VERSION 5.8 ;
BUSBITCHARS "[]" ;
DIVIDERCHAR "/" ;
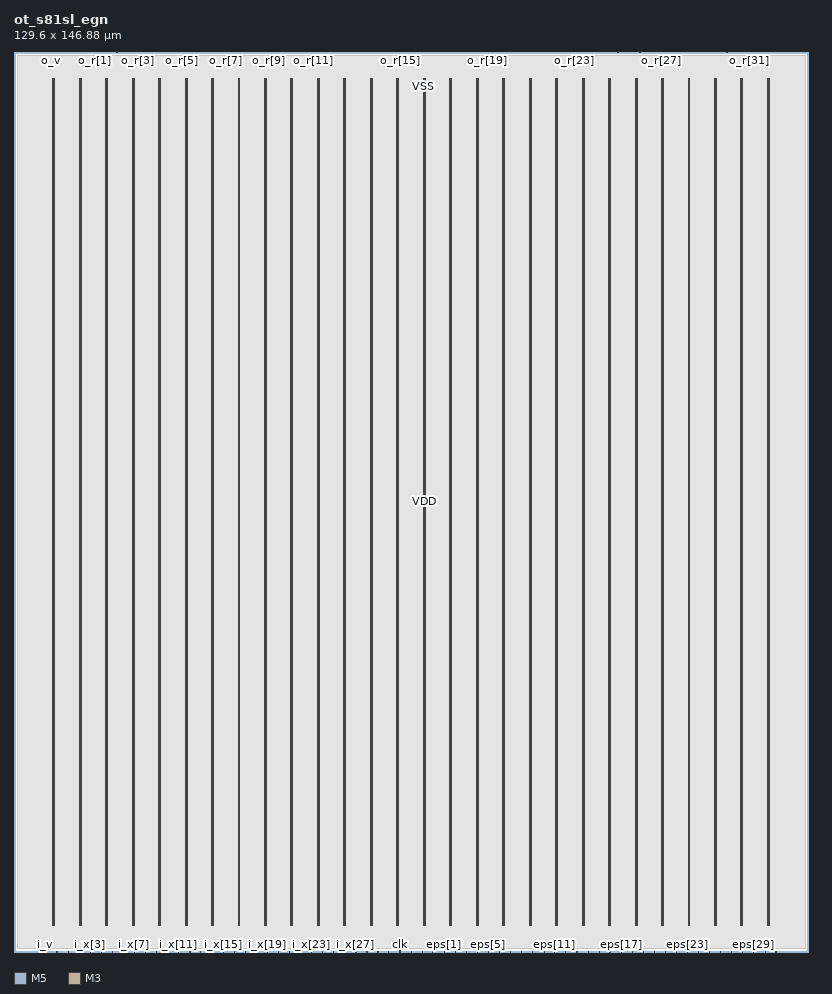
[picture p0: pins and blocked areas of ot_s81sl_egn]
MACRO ot_s81sl_egn
  CLASS BLOCK ;
  ORIGIN 0 0 ;
  FOREIGN ot_s81sl_egn 0 0 ;
  SIZE 129.600 BY 146.880 ;
  SYMMETRY X Y ;
  PIN clk
    DIRECTION INPUT ;
    USE SIGNAL ;
    PORT
      LAYER M5 ;
        RECT 62.9640 0.0000 63.0120 0.4800 ;
    END
  END clk
  PIN eps[0]
    DIRECTION INPUT ;
    USE SIGNAL ;
    PORT
      LAYER M5 ;
        RECT 68.3520 0.0000 68.3760 0.0840 ;
    END
  END eps[0]
  PIN eps[10]
    DIRECTION INPUT ;
    USE SIGNAL ;
    PORT
      LAYER M5 ;
        RECT 86.4960 0.0000 86.5200 0.0840 ;
    END
  END eps[10]
  PIN eps[11]
    DIRECTION INPUT ;
    USE SIGNAL ;
    PORT
      LAYER M3 ;
        RECT 88.2720 0.0000 88.2900 0.0380 ;
    END
  END eps[11]
  PIN eps[12]
    DIRECTION INPUT ;
    USE SIGNAL ;
    PORT
      LAYER M5 ;
        RECT 90.0480 0.0000 90.0720 0.0840 ;
    END
  END eps[12]
  PIN eps[13]
    DIRECTION INPUT ;
    USE SIGNAL ;
    PORT
      LAYER M3 ;
        RECT 91.8720 0.0000 91.8900 0.0380 ;
    END
  END eps[13]
  PIN eps[14]
    DIRECTION INPUT ;
    USE SIGNAL ;
    PORT
      LAYER M5 ;
        RECT 93.6960 0.0000 93.7200 0.0840 ;
    END
  END eps[14]
  PIN eps[15]
    DIRECTION INPUT ;
    USE SIGNAL ;
    PORT
      LAYER M3 ;
        RECT 95.4720 0.0000 95.4900 0.0380 ;
    END
  END eps[15]
  PIN eps[16]
    DIRECTION INPUT ;
    USE SIGNAL ;
    PORT
      LAYER M5 ;
        RECT 97.2480 0.0000 97.2720 0.0840 ;
    END
  END eps[16]
  PIN eps[17]
    DIRECTION INPUT ;
    USE SIGNAL ;
    PORT
      LAYER M3 ;
        RECT 99.0720 0.0000 99.0900 0.0380 ;
    END
  END eps[17]
  PIN eps[18]
    DIRECTION INPUT ;
    USE SIGNAL ;
    PORT
      LAYER M5 ;
        RECT 100.8960 0.0000 100.9200 0.0840 ;
    END
  END eps[18]
  PIN eps[19]
    DIRECTION INPUT ;
    USE SIGNAL ;
    PORT
      LAYER M3 ;
        RECT 102.6720 0.0000 102.6900 0.0380 ;
    END
  END eps[19]
  PIN eps[1]
    DIRECTION INPUT ;
    USE SIGNAL ;
    PORT
      LAYER M3 ;
        RECT 70.2000 0.0000 70.2180 0.0380 ;
    END
  END eps[1]
  PIN eps[20]
    DIRECTION INPUT ;
    USE SIGNAL ;
    PORT
      LAYER M5 ;
        RECT 104.5440 0.0000 104.5680 0.0840 ;
    END
  END eps[20]
  PIN eps[21]
    DIRECTION INPUT ;
    USE SIGNAL ;
    PORT
      LAYER M3 ;
        RECT 106.3440 0.0000 106.3620 0.0380 ;
    END
  END eps[21]
  PIN eps[22]
    DIRECTION INPUT ;
    USE SIGNAL ;
    PORT
      LAYER M5 ;
        RECT 108.0960 0.0000 108.1200 0.0840 ;
    END
  END eps[22]
  PIN eps[23]
    DIRECTION INPUT ;
    USE SIGNAL ;
    PORT
      LAYER M3 ;
        RECT 109.9440 0.0000 109.9620 0.0380 ;
    END
  END eps[23]
  PIN eps[24]
    DIRECTION INPUT ;
    USE SIGNAL ;
    PORT
      LAYER M5 ;
        RECT 111.7440 0.0000 111.7680 0.0840 ;
    END
  END eps[24]
  PIN eps[25]
    DIRECTION INPUT ;
    USE SIGNAL ;
    PORT
      LAYER M3 ;
        RECT 113.5440 0.0000 113.5620 0.0380 ;
    END
  END eps[25]
  PIN eps[26]
    DIRECTION INPUT ;
    USE SIGNAL ;
    PORT
      LAYER M5 ;
        RECT 115.2960 0.0000 115.3200 0.0840 ;
    END
  END eps[26]
  PIN eps[27]
    DIRECTION INPUT ;
    USE SIGNAL ;
    PORT
      LAYER M3 ;
        RECT 117.1440 0.0000 117.1620 0.0380 ;
    END
  END eps[27]
  PIN eps[28]
    DIRECTION INPUT ;
    USE SIGNAL ;
    PORT
      LAYER M5 ;
        RECT 118.9440 0.0000 118.9680 0.0840 ;
    END
  END eps[28]
  PIN eps[29]
    DIRECTION INPUT ;
    USE SIGNAL ;
    PORT
      LAYER M3 ;
        RECT 120.7440 0.0000 120.7620 0.0380 ;
    END
  END eps[29]
  PIN eps[2]
    DIRECTION INPUT ;
    USE SIGNAL ;
    PORT
      LAYER M5 ;
        RECT 72.0000 0.0000 72.0240 0.0840 ;
    END
  END eps[2]
  PIN eps[30]
    DIRECTION INPUT ;
    USE SIGNAL ;
    PORT
      LAYER M5 ;
        RECT 122.5920 0.0000 122.6160 0.0840 ;
    END
  END eps[30]
  PIN eps[31]
    DIRECTION INPUT ;
    USE SIGNAL ;
    PORT
      LAYER M3 ;
        RECT 124.3440 0.0000 124.3620 0.0380 ;
    END
  END eps[31]
  PIN eps[3]
    DIRECTION INPUT ;
    USE SIGNAL ;
    PORT
      LAYER M3 ;
        RECT 73.8000 0.0000 73.8180 0.0380 ;
    END
  END eps[3]
  PIN eps[4]
    DIRECTION INPUT ;
    USE SIGNAL ;
    PORT
      LAYER M5 ;
        RECT 75.6480 0.0000 75.6720 0.0840 ;
    END
  END eps[4]
  PIN eps[5]
    DIRECTION INPUT ;
    USE SIGNAL ;
    PORT
      LAYER M3 ;
        RECT 77.4000 0.0000 77.4180 0.0380 ;
    END
  END eps[5]
  PIN eps[6]
    DIRECTION INPUT ;
    USE SIGNAL ;
    PORT
      LAYER M5 ;
        RECT 79.2000 0.0000 79.2240 0.0840 ;
    END
  END eps[6]
  PIN eps[7]
    DIRECTION INPUT ;
    USE SIGNAL ;
    PORT
      LAYER M3 ;
        RECT 81.0720 0.0000 81.0900 0.0380 ;
    END
  END eps[7]
  PIN eps[8]
    DIRECTION INPUT ;
    USE SIGNAL ;
    PORT
      LAYER M5 ;
        RECT 82.8480 0.0000 82.8720 0.0840 ;
    END
  END eps[8]
  PIN eps[9]
    DIRECTION INPUT ;
    USE SIGNAL ;
    PORT
      LAYER M3 ;
        RECT 84.6720 0.0000 84.6900 0.0380 ;
    END
  END eps[9]
  PIN i_v
    DIRECTION INPUT ;
    USE SIGNAL ;
    PORT
      LAYER M3 ;
        RECT 5.1840 0.0000 5.2020 0.0380 ;
    END
  END i_v
  PIN i_x[0]
    DIRECTION INPUT ;
    USE SIGNAL ;
    PORT
      LAYER M5 ;
        RECT 7.0080 0.0000 7.0320 0.0840 ;
    END
  END i_x[0]
  PIN i_x[10]
    DIRECTION INPUT ;
    USE SIGNAL ;
    PORT
      LAYER M5 ;
        RECT 25.0560 0.0000 25.0800 0.0840 ;
    END
  END i_x[10]
  PIN i_x[11]
    DIRECTION INPUT ;
    USE SIGNAL ;
    PORT
      LAYER M3 ;
        RECT 26.8560 0.0000 26.8740 0.0380 ;
    END
  END i_x[11]
  PIN i_x[12]
    DIRECTION INPUT ;
    USE SIGNAL ;
    PORT
      LAYER M5 ;
        RECT 28.7040 0.0000 28.7280 0.0840 ;
    END
  END i_x[12]
  PIN i_x[13]
    DIRECTION INPUT ;
    USE SIGNAL ;
    PORT
      LAYER M3 ;
        RECT 30.4560 0.0000 30.4740 0.0380 ;
    END
  END i_x[13]
  PIN i_x[14]
    DIRECTION INPUT ;
    USE SIGNAL ;
    PORT
      LAYER M5 ;
        RECT 32.2560 0.0000 32.2800 0.0840 ;
    END
  END i_x[14]
  PIN i_x[15]
    DIRECTION INPUT ;
    USE SIGNAL ;
    PORT
      LAYER M3 ;
        RECT 34.1280 0.0000 34.1460 0.0380 ;
    END
  END i_x[15]
  PIN i_x[16]
    DIRECTION INPUT ;
    USE SIGNAL ;
    PORT
      LAYER M5 ;
        RECT 35.9040 0.0000 35.9280 0.0840 ;
    END
  END i_x[16]
  PIN i_x[17]
    DIRECTION INPUT ;
    USE SIGNAL ;
    PORT
      LAYER M3 ;
        RECT 37.7280 0.0000 37.7460 0.0380 ;
    END
  END i_x[17]
  PIN i_x[18]
    DIRECTION INPUT ;
    USE SIGNAL ;
    PORT
      LAYER M5 ;
        RECT 39.5520 0.0000 39.5760 0.0840 ;
    END
  END i_x[18]
  PIN i_x[19]
    DIRECTION INPUT ;
    USE SIGNAL ;
    PORT
      LAYER M3 ;
        RECT 41.3280 0.0000 41.3460 0.0380 ;
    END
  END i_x[19]
  PIN i_x[1]
    DIRECTION INPUT ;
    USE SIGNAL ;
    PORT
      LAYER M3 ;
        RECT 8.8560 0.0000 8.8740 0.0380 ;
    END
  END i_x[1]
  PIN i_x[20]
    DIRECTION INPUT ;
    USE SIGNAL ;
    PORT
      LAYER M5 ;
        RECT 43.1040 0.0000 43.1280 0.0840 ;
    END
  END i_x[20]
  PIN i_x[21]
    DIRECTION INPUT ;
    USE SIGNAL ;
    PORT
      LAYER M3 ;
        RECT 44.9280 0.0000 44.9460 0.0380 ;
    END
  END i_x[21]
  PIN i_x[22]
    DIRECTION INPUT ;
    USE SIGNAL ;
    PORT
      LAYER M5 ;
        RECT 46.7520 0.0000 46.7760 0.0840 ;
    END
  END i_x[22]
  PIN i_x[23]
    DIRECTION INPUT ;
    USE SIGNAL ;
    PORT
      LAYER M3 ;
        RECT 48.5280 0.0000 48.5460 0.0380 ;
    END
  END i_x[23]
  PIN i_x[24]
    DIRECTION INPUT ;
    USE SIGNAL ;
    PORT
      LAYER M5 ;
        RECT 50.3040 0.0000 50.3280 0.0840 ;
    END
  END i_x[24]
  PIN i_x[25]
    DIRECTION INPUT ;
    USE SIGNAL ;
    PORT
      LAYER M3 ;
        RECT 52.1280 0.0000 52.1460 0.0380 ;
    END
  END i_x[25]
  PIN i_x[26]
    DIRECTION INPUT ;
    USE SIGNAL ;
    PORT
      LAYER M5 ;
        RECT 53.9520 0.0000 53.9760 0.0840 ;
    END
  END i_x[26]
  PIN i_x[27]
    DIRECTION INPUT ;
    USE SIGNAL ;
    PORT
      LAYER M3 ;
        RECT 55.8000 0.0000 55.8180 0.0380 ;
    END
  END i_x[27]
  PIN i_x[28]
    DIRECTION INPUT ;
    USE SIGNAL ;
    PORT
      LAYER M5 ;
        RECT 57.6000 0.0000 57.6240 0.0840 ;
    END
  END i_x[28]
  PIN i_x[29]
    DIRECTION INPUT ;
    USE SIGNAL ;
    PORT
      LAYER M3 ;
        RECT 59.4000 0.0000 59.4180 0.0380 ;
    END
  END i_x[29]
  PIN i_x[2]
    DIRECTION INPUT ;
    USE SIGNAL ;
    PORT
      LAYER M5 ;
        RECT 10.6560 0.0000 10.6800 0.0840 ;
    END
  END i_x[2]
  PIN i_x[30]
    DIRECTION INPUT ;
    USE SIGNAL ;
    PORT
      LAYER M5 ;
        RECT 61.1520 0.0000 61.1760 0.0840 ;
    END
  END i_x[30]
  PIN i_x[31]
    DIRECTION INPUT ;
    USE SIGNAL ;
    PORT
      LAYER M3 ;
        RECT 66.6000 0.0000 66.6180 0.0380 ;
    END
  END i_x[31]
  PIN i_x[3]
    DIRECTION INPUT ;
    USE SIGNAL ;
    PORT
      LAYER M3 ;
        RECT 12.4560 0.0000 12.4740 0.0380 ;
    END
  END i_x[3]
  PIN i_x[4]
    DIRECTION INPUT ;
    USE SIGNAL ;
    PORT
      LAYER M5 ;
        RECT 14.2080 0.0000 14.2320 0.0840 ;
    END
  END i_x[4]
  PIN i_x[5]
    DIRECTION INPUT ;
    USE SIGNAL ;
    PORT
      LAYER M3 ;
        RECT 16.0560 0.0000 16.0740 0.0380 ;
    END
  END i_x[5]
  PIN i_x[6]
    DIRECTION INPUT ;
    USE SIGNAL ;
    PORT
      LAYER M5 ;
        RECT 17.8560 0.0000 17.8800 0.0840 ;
    END
  END i_x[6]
  PIN i_x[7]
    DIRECTION INPUT ;
    USE SIGNAL ;
    PORT
      LAYER M3 ;
        RECT 19.6560 0.0000 19.6740 0.0380 ;
    END
  END i_x[7]
  PIN i_x[8]
    DIRECTION INPUT ;
    USE SIGNAL ;
    PORT
      LAYER M5 ;
        RECT 21.5040 0.0000 21.5280 0.0840 ;
    END
  END i_x[8]
  PIN i_x[9]
    DIRECTION INPUT ;
    USE SIGNAL ;
    PORT
      LAYER M3 ;
        RECT 23.2560 0.0000 23.2740 0.0380 ;
    END
  END i_x[9]
  PIN o_f
    DIRECTION OUTPUT ;
    USE SIGNAL ;
    PORT
      LAYER M5 ;
        RECT 123.4560 146.7960 123.4800 146.8800 ;
    END
  END o_f
  PIN o_r[0]
    DIRECTION OUTPUT ;
    USE SIGNAL ;
    PORT
      LAYER M5 ;
        RECT 9.6000 146.7960 9.6240 146.8800 ;
    END
  END o_r[0]
  PIN o_r[10]
    DIRECTION OUTPUT ;
    USE SIGNAL ;
    PORT
      LAYER M5 ;
        RECT 45.2160 146.7960 45.2400 146.8800 ;
    END
  END o_r[10]
  PIN o_r[11]
    DIRECTION OUTPUT ;
    USE SIGNAL ;
    PORT
      LAYER M3 ;
        RECT 48.8160 146.8420 48.8340 146.8800 ;
    END
  END o_r[11]
  PIN o_r[12]
    DIRECTION OUTPUT ;
    USE SIGNAL ;
    PORT
      LAYER M5 ;
        RECT 52.3200 146.7960 52.3440 146.8800 ;
    END
  END o_r[12]
  PIN o_r[13]
    DIRECTION OUTPUT ;
    USE SIGNAL ;
    PORT
      LAYER M3 ;
        RECT 55.8720 146.8420 55.8900 146.8800 ;
    END
  END o_r[13]
  PIN o_r[14]
    DIRECTION OUTPUT ;
    USE SIGNAL ;
    PORT
      LAYER M5 ;
        RECT 59.4240 146.7960 59.4480 146.8800 ;
    END
  END o_r[14]
  PIN o_r[15]
    DIRECTION OUTPUT ;
    USE SIGNAL ;
    PORT
      LAYER M3 ;
        RECT 63.0000 146.8420 63.0180 146.8800 ;
    END
  END o_r[15]
  PIN o_r[16]
    DIRECTION OUTPUT ;
    USE SIGNAL ;
    PORT
      LAYER M5 ;
        RECT 66.5280 146.7960 66.5520 146.8800 ;
    END
  END o_r[16]
  PIN o_r[17]
    DIRECTION OUTPUT ;
    USE SIGNAL ;
    PORT
      LAYER M3 ;
        RECT 70.1280 146.8420 70.1460 146.8800 ;
    END
  END o_r[17]
  PIN o_r[18]
    DIRECTION OUTPUT ;
    USE SIGNAL ;
    PORT
      LAYER M5 ;
        RECT 73.7280 146.7960 73.7520 146.8800 ;
    END
  END o_r[18]
  PIN o_r[19]
    DIRECTION OUTPUT ;
    USE SIGNAL ;
    PORT
      LAYER M3 ;
        RECT 77.2560 146.8420 77.2740 146.8800 ;
    END
  END o_r[19]
  PIN o_r[1]
    DIRECTION OUTPUT ;
    USE SIGNAL ;
    PORT
      LAYER M3 ;
        RECT 13.1760 146.8420 13.1940 146.8800 ;
    END
  END o_r[1]
  PIN o_r[20]
    DIRECTION OUTPUT ;
    USE SIGNAL ;
    PORT
      LAYER M5 ;
        RECT 80.8320 146.7960 80.8560 146.8800 ;
    END
  END o_r[20]
  PIN o_r[21]
    DIRECTION OUTPUT ;
    USE SIGNAL ;
    PORT
      LAYER M3 ;
        RECT 84.3840 146.8420 84.4020 146.8800 ;
    END
  END o_r[21]
  PIN o_r[22]
    DIRECTION OUTPUT ;
    USE SIGNAL ;
    PORT
      LAYER M5 ;
        RECT 87.9360 146.7960 87.9600 146.8800 ;
    END
  END o_r[22]
  PIN o_r[23]
    DIRECTION OUTPUT ;
    USE SIGNAL ;
    PORT
      LAYER M3 ;
        RECT 91.4400 146.8420 91.4580 146.8800 ;
    END
  END o_r[23]
  PIN o_r[24]
    DIRECTION OUTPUT ;
    USE SIGNAL ;
    PORT
      LAYER M5 ;
        RECT 95.0400 146.7960 95.0640 146.8800 ;
    END
  END o_r[24]
  PIN o_r[25]
    DIRECTION OUTPUT ;
    USE SIGNAL ;
    PORT
      LAYER M3 ;
        RECT 98.5680 146.8420 98.5860 146.8800 ;
    END
  END o_r[25]
  PIN o_r[26]
    DIRECTION OUTPUT ;
    USE SIGNAL ;
    PORT
      LAYER M5 ;
        RECT 102.1440 146.7960 102.1680 146.8800 ;
    END
  END o_r[26]
  PIN o_r[27]
    DIRECTION OUTPUT ;
    USE SIGNAL ;
    PORT
      LAYER M3 ;
        RECT 105.6960 146.8420 105.7140 146.8800 ;
    END
  END o_r[27]
  PIN o_r[28]
    DIRECTION OUTPUT ;
    USE SIGNAL ;
    PORT
      LAYER M5 ;
        RECT 109.2480 146.7960 109.2720 146.8800 ;
    END
  END o_r[28]
  PIN o_r[29]
    DIRECTION OUTPUT ;
    USE SIGNAL ;
    PORT
      LAYER M3 ;
        RECT 112.8240 146.8420 112.8420 146.8800 ;
    END
  END o_r[29]
  PIN o_r[2]
    DIRECTION OUTPUT ;
    USE SIGNAL ;
    PORT
      LAYER M5 ;
        RECT 16.8000 146.7960 16.8240 146.8800 ;
    END
  END o_r[2]
  PIN o_r[30]
    DIRECTION OUTPUT ;
    USE SIGNAL ;
    PORT
      LAYER M5 ;
        RECT 116.3520 146.7960 116.3760 146.8800 ;
    END
  END o_r[30]
  PIN o_r[31]
    DIRECTION OUTPUT ;
    USE SIGNAL ;
    PORT
      LAYER M3 ;
        RECT 119.9520 146.8420 119.9700 146.8800 ;
    END
  END o_r[31]
  PIN o_r[3]
    DIRECTION OUTPUT ;
    USE SIGNAL ;
    PORT
      LAYER M3 ;
        RECT 20.3040 146.8420 20.3220 146.8800 ;
    END
  END o_r[3]
  PIN o_r[4]
    DIRECTION OUTPUT ;
    USE SIGNAL ;
    PORT
      LAYER M5 ;
        RECT 23.9040 146.7960 23.9280 146.8800 ;
    END
  END o_r[4]
  PIN o_r[5]
    DIRECTION OUTPUT ;
    USE SIGNAL ;
    PORT
      LAYER M3 ;
        RECT 27.4320 146.8420 27.4500 146.8800 ;
    END
  END o_r[5]
  PIN o_r[6]
    DIRECTION OUTPUT ;
    USE SIGNAL ;
    PORT
      LAYER M5 ;
        RECT 31.0080 146.7960 31.0320 146.8800 ;
    END
  END o_r[6]
  PIN o_r[7]
    DIRECTION OUTPUT ;
    USE SIGNAL ;
    PORT
      LAYER M3 ;
        RECT 34.5600 146.8420 34.5780 146.8800 ;
    END
  END o_r[7]
  PIN o_r[8]
    DIRECTION OUTPUT ;
    USE SIGNAL ;
    PORT
      LAYER M5 ;
        RECT 38.1120 146.7960 38.1360 146.8800 ;
    END
  END o_r[8]
  PIN o_r[9]
    DIRECTION OUTPUT ;
    USE SIGNAL ;
    PORT
      LAYER M3 ;
        RECT 41.6880 146.8420 41.7060 146.8800 ;
    END
  END o_r[9]
  PIN o_v
    DIRECTION OUTPUT ;
    USE SIGNAL ;
    PORT
      LAYER M3 ;
        RECT 6.1200 146.8420 6.1380 146.8800 ;
    END
  END o_v
  PIN rst_n
    DIRECTION INPUT ;
    USE SIGNAL ;
    PORT
      LAYER M5 ;
        RECT 64.8000 0.0000 64.8240 0.0840 ;
    END
  END rst_n
  PIN VSS
    DIRECTION INOUT ;
    USE GROUND ;
    PORT
      LAYER M5 ;
        RECT 6.324000 4.320000 6.444000 142.560000 ;
        RECT 10.644000 4.320000 10.764000 142.560000 ;
        RECT 14.964000 4.320000 15.084000 142.560000 ;
        RECT 19.284000 4.320000 19.404000 142.560000 ;
        RECT 23.604000 4.320000 23.724000 142.560000 ;
        RECT 27.924000 4.320000 28.044000 142.560000 ;
        RECT 32.244000 4.320000 32.364000 142.560000 ;
        RECT 36.564000 4.320000 36.684000 142.560000 ;
        RECT 40.884000 4.320000 41.004000 142.560000 ;
        RECT 45.204000 4.320000 45.324000 142.560000 ;
        RECT 49.524000 4.320000 49.644000 142.560000 ;
        RECT 53.844000 4.320000 53.964000 142.560000 ;
        RECT 58.164000 4.320000 58.284000 142.560000 ;
        RECT 62.484000 4.320000 62.604000 142.560000 ;
        RECT 66.804000 4.320000 66.924000 142.560000 ;
        RECT 71.124000 4.320000 71.244000 142.560000 ;
        RECT 75.444000 4.320000 75.564000 142.560000 ;
        RECT 79.764000 4.320000 79.884000 142.560000 ;
        RECT 84.084000 4.320000 84.204000 142.560000 ;
        RECT 88.404000 4.320000 88.524000 142.560000 ;
        RECT 92.724000 4.320000 92.844000 142.560000 ;
        RECT 97.044000 4.320000 97.164000 142.560000 ;
        RECT 101.364000 4.320000 101.484000 142.560000 ;
        RECT 105.684000 4.320000 105.804000 142.560000 ;
        RECT 110.004000 4.320000 110.124000 142.560000 ;
        RECT 114.324000 4.320000 114.444000 142.560000 ;
        RECT 118.644000 4.320000 118.764000 142.560000 ;
        RECT 122.964000 4.320000 123.084000 142.560000 ;
    END
  END VSS
  PIN VDD
    DIRECTION INOUT ;
    USE POWER ;
    PORT
      LAYER M5 ;
        RECT 6.516000 4.320000 6.636000 142.560000 ;
        RECT 10.836000 4.320000 10.956000 142.560000 ;
        RECT 15.156000 4.320000 15.276000 142.560000 ;
        RECT 19.476000 4.320000 19.596000 142.560000 ;
        RECT 23.796000 4.320000 23.916000 142.560000 ;
        RECT 28.116000 4.320000 28.236000 142.560000 ;
        RECT 32.436000 4.320000 32.556000 142.560000 ;
        RECT 36.756000 4.320000 36.876000 142.560000 ;
        RECT 41.076000 4.320000 41.196000 142.560000 ;
        RECT 45.396000 4.320000 45.516000 142.560000 ;
        RECT 49.716000 4.320000 49.836000 142.560000 ;
        RECT 54.036000 4.320000 54.156000 142.560000 ;
        RECT 58.356000 4.320000 58.476000 142.560000 ;
        RECT 62.676000 4.320000 62.796000 142.560000 ;
        RECT 66.996000 4.320000 67.116000 142.560000 ;
        RECT 71.316000 4.320000 71.436000 142.560000 ;
        RECT 75.636000 4.320000 75.756000 142.560000 ;
        RECT 79.956000 4.320000 80.076000 142.560000 ;
        RECT 84.276000 4.320000 84.396000 142.560000 ;
        RECT 88.596000 4.320000 88.716000 142.560000 ;
        RECT 92.916000 4.320000 93.036000 142.560000 ;
        RECT 97.236000 4.320000 97.356000 142.560000 ;
        RECT 101.556000 4.320000 101.676000 142.560000 ;
        RECT 105.876000 4.320000 105.996000 142.560000 ;
        RECT 110.196000 4.320000 110.316000 142.560000 ;
        RECT 114.516000 4.320000 114.636000 142.560000 ;
        RECT 118.836000 4.320000 118.956000 142.560000 ;
        RECT 123.156000 4.320000 123.276000 142.560000 ;
    END
  END VDD
  OBS
    LAYER M1 ;
      RECT 0.5 0.5 129.100 146.380 ;
    LAYER M2 ;
      RECT 0.5 0.5 129.100 146.380 ;
    LAYER M3 ;
      RECT 0.5 0.5 129.100 146.380 ;
    LAYER M4 ;
      RECT 0.5 0.5 129.100 146.380 ;
    LAYER M5 ;
      RECT 0.5 0.5 129.100 146.380 ;
    LAYER M6 ;
      RECT 0.5 0.5 129.100 146.380 ;
    LAYER M7 ;
      RECT 0.5 0.5 129.100 146.380 ;
  END
END ot_s81sl_egn
END LIBRARY
